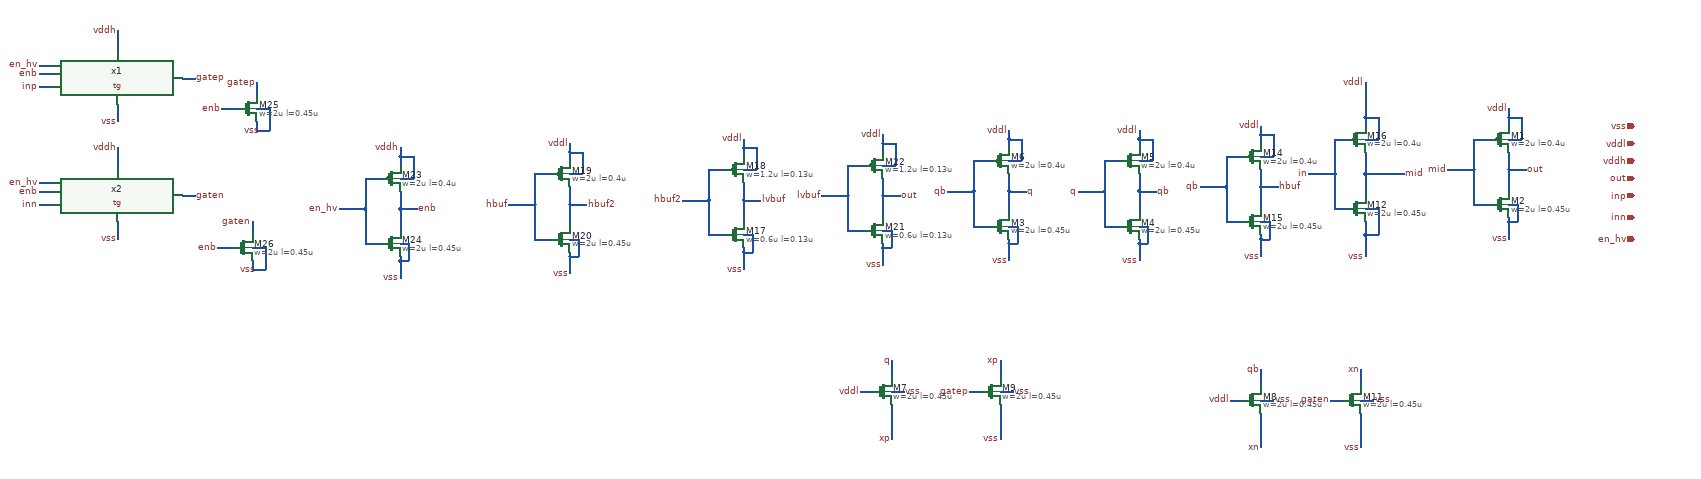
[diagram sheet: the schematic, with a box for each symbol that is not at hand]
v {xschem version=3.4.8RC file_version=1.3}
G {}
K {}
V {}
S {}
F {}
E {}
N 710 -410 710 -360 {lab=out
spice_ignore=true}
N 710 -290 710 -250 {lab=vss
spice_ignore=true}
N 710 -530 710 -510 {lab=vddl
spice_ignore=true}
N 630 -480 670 -480 {lab=mid
spice_ignore=true}
N 630 -410 630 -330 {lab=mid
spice_ignore=true}
N 630 -330 670 -330 {lab=mid
spice_ignore=true}
N 570 -410 630 -410 {lab=mid
spice_ignore=true}
N 630 -480 630 -410 {lab=mid
spice_ignore=true}
N 710 -480 740 -480 {lab=vddl
spice_ignore=true}
N 740 -530 740 -480 {lab=vddl
spice_ignore=true}
N 710 -530 740 -530 {lab=vddl
spice_ignore=true}
N 710 -550 710 -530 {lab=vddl
spice_ignore=true}
N 710 -330 730 -330 {lab=vss
spice_ignore=true}
N 730 -330 730 -290 {lab=vss
spice_ignore=true}
N 710 -290 730 -290 {lab=vss
spice_ignore=true}
N 710 -300 710 -290 {lab=vss
spice_ignore=true}
N 710 -410 750 -410 {lab=out
spice_ignore=true}
N 710 -450 710 -410 {lab=out
spice_ignore=true}
N 380 -400 380 -350 {
lab=mid
spice_ignore=true}
N 380 -530 380 -510 {
lab=vddl
spice_ignore=true}
N 380 -260 380 -210 {
lab=vss
spice_ignore=true}
N 380 -320 410 -320 {
lab=vss
spice_ignore=true}
N 310 -480 340 -480 {
lab=in
spice_ignore=true}
N 310 -400 310 -320 {
lab=in
spice_ignore=true}
N 310 -320 340 -320 {
lab=in
spice_ignore=true}
N 380 -480 410 -480 {
lab=vddl
spice_ignore=true}
N 410 -530 410 -480 {
lab=vddl
spice_ignore=true}
N 380 -530 410 -530 {
lab=vddl
spice_ignore=true}
N 410 -320 410 -260 {
lab=vss
spice_ignore=true}
N 380 -260 410 -260 {
lab=vss
spice_ignore=true}
N 250 -400 310 -400 {
lab=in
spice_ignore=true}
N 380 -400 470 -400 {
lab=mid
spice_ignore=true}
N 380 -610 380 -530 {
lab=vddl
spice_ignore=true}
N 380 -290 380 -260 {
lab=vss
spice_ignore=true}
N 310 -480 310 -400 {
lab=in
spice_ignore=true}
N 380 -450 380 -400 {
lab=mid
spice_ignore=true}
N -440 -360 -440 -310 {lab=q}
N -440 -240 -440 -200 {lab=vss}
N -440 -480 -440 -460 {lab=vddl}
N -520 -430 -480 -430 {lab=qb}
N -520 -360 -520 -280 {lab=qb}
N -520 -280 -480 -280 {lab=qb}
N -580 -360 -520 -360 {lab=qb}
N -520 -430 -520 -360 {lab=qb}
N -440 -430 -410 -430 {lab=vddl}
N -410 -480 -410 -430 {lab=vddl}
N -440 -480 -410 -480 {lab=vddl}
N -440 -500 -440 -480 {lab=vddl}
N -440 -280 -420 -280 {lab=vss}
N -420 -280 -420 -240 {lab=vss}
N -440 -240 -420 -240 {lab=vss}
N -440 -250 -440 -240 {lab=vss}
N -440 -360 -400 -360 {lab=q}
N -440 -400 -440 -360 {lab=q}
N -140 -360 -140 -310 {lab=qb}
N -140 -240 -140 -200 {lab=vss}
N -140 -480 -140 -460 {lab=vddl}
N -220 -430 -180 -430 {lab=q}
N -220 -360 -220 -280 {lab=q}
N -220 -280 -180 -280 {lab=q}
N -280 -360 -220 -360 {lab=q}
N -220 -430 -220 -360 {lab=q}
N -140 -430 -110 -430 {lab=vddl}
N -110 -480 -110 -430 {lab=vddl}
N -140 -480 -110 -480 {lab=vddl}
N -140 -500 -140 -480 {lab=vddl}
N -140 -280 -120 -280 {lab=vss}
N -120 -280 -120 -240 {lab=vss}
N -140 -240 -120 -240 {lab=vss}
N -140 -250 -140 -240 {lab=vss}
N -140 -360 -100 -360 {lab=qb}
N -140 -400 -140 -360 {lab=qb}
N -710 100 -680 100 {
lab=vss
}
N -780 100 -750 100 {
lab=vddl
}
N -710 130 -710 210 {
lab=xp
}
N -710 30 -710 70 {lab=q}
N -460 100 -430 100 {
lab=vss
}
N -530 100 -500 100 {
lab=gatep
}
N -460 130 -460 210 {
lab=vss
}
N -460 30 -460 70 {lab=xp}
N 140 120 170 120 {
lab=vss
}
N 70 120 100 120 {
lab=vddl
}
N 140 150 140 230 {
lab=xn
}
N 140 50 140 90 {lab=qb}
N 370 120 400 120 {
lab=vss
}
N 300 120 330 120 {
lab=gaten
}
N 370 150 370 230 {
lab=vss
}
N 370 50 370 90 {lab=xn}
N 140 -370 140 -320 {lab=hbuf}
N 140 -250 140 -210 {lab=vss}
N 140 -490 140 -470 {lab=vddl}
N 60 -440 100 -440 {lab=qb}
N 60 -370 60 -290 {lab=qb}
N 60 -290 100 -290 {lab=qb}
N 0 -370 60 -370 {lab=qb}
N 60 -440 60 -370 {lab=qb}
N 140 -440 170 -440 {lab=vddl}
N 170 -490 170 -440 {lab=vddl}
N 140 -490 170 -490 {lab=vddl}
N 140 -510 140 -490 {lab=vddl}
N 140 -290 160 -290 {lab=vss}
N 160 -290 160 -250 {lab=vss}
N 140 -250 160 -250 {lab=vss}
N 140 -260 140 -250 {lab=vss}
N 140 -370 180 -370 {lab=hbuf}
N 140 -410 140 -370 {lab=hbuf}
N -1050 -340 -1050 -290 {lab=lvbuf}
N -1050 -220 -1050 -180 {lab=vss}
N -1050 -460 -1050 -440 {lab=vddl}
N -1130 -410 -1090 -410 {lab=hbuf2}
N -1130 -340 -1130 -260 {lab=hbuf2}
N -1130 -260 -1090 -260 {lab=hbuf2}
N -1190 -340 -1130 -340 {lab=hbuf2}
N -1130 -410 -1130 -340 {lab=hbuf2}
N -1050 -410 -1020 -410 {lab=vddl}
N -1020 -460 -1020 -410 {lab=vddl}
N -1050 -460 -1020 -460 {lab=vddl}
N -1050 -480 -1050 -460 {lab=vddl}
N -1050 -260 -1030 -260 {lab=vss}
N -1030 -260 -1030 -220 {lab=vss}
N -1050 -220 -1030 -220 {lab=vss}
N -1050 -230 -1050 -220 {lab=vss}
N -1050 -340 -1010 -340 {lab=lvbuf}
N -1050 -380 -1050 -340 {lab=lvbuf}
N -1450 -330 -1450 -280 {lab=hbuf2}
N -1450 -210 -1450 -170 {lab=vss}
N -1450 -450 -1450 -430 {lab=vddl}
N -1530 -400 -1490 -400 {lab=hbuf}
N -1530 -330 -1530 -250 {lab=hbuf}
N -1530 -250 -1490 -250 {lab=hbuf}
N -1590 -330 -1530 -330 {lab=hbuf}
N -1530 -400 -1530 -330 {lab=hbuf}
N -1450 -400 -1420 -400 {lab=vddl}
N -1420 -450 -1420 -400 {lab=vddl}
N -1450 -450 -1420 -450 {lab=vddl}
N -1450 -470 -1450 -450 {lab=vddl}
N -1450 -250 -1430 -250 {lab=vss}
N -1430 -250 -1430 -210 {lab=vss}
N -1450 -210 -1430 -210 {lab=vss}
N -1450 -220 -1450 -210 {lab=vss}
N -1450 -330 -1410 -330 {lab=hbuf2}
N -1450 -370 -1450 -330 {lab=hbuf2}
N -730 -350 -730 -300 {lab=out}
N -730 -230 -730 -190 {lab=vss}
N -730 -470 -730 -450 {lab=vddl}
N -810 -420 -770 -420 {lab=lvbuf}
N -810 -350 -810 -270 {lab=lvbuf}
N -810 -270 -770 -270 {lab=lvbuf}
N -870 -350 -810 -350 {lab=lvbuf}
N -810 -420 -810 -350 {lab=lvbuf}
N -730 -420 -700 -420 {lab=vddl}
N -700 -470 -700 -420 {lab=vddl}
N -730 -470 -700 -470 {lab=vddl}
N -730 -490 -730 -470 {lab=vddl}
N -730 -270 -710 -270 {lab=vss}
N -710 -270 -710 -230 {lab=vss}
N -730 -230 -710 -230 {lab=vss}
N -730 -240 -730 -230 {lab=vss}
N -730 -350 -690 -350 {lab=out}
N -730 -390 -730 -350 {lab=out}
N -1840 -320 -1840 -270 {lab=enb}
N -1840 -200 -1840 -160 {lab=vss}
N -1840 -440 -1840 -420 {lab=vddh}
N -1920 -390 -1880 -390 {lab=en_hv}
N -1920 -320 -1920 -240 {lab=en_hv}
N -1920 -240 -1880 -240 {lab=en_hv}
N -1980 -320 -1920 -320 {lab=en_hv}
N -1920 -390 -1920 -320 {lab=en_hv}
N -1840 -390 -1810 -390 {lab=vddh}
N -1810 -440 -1810 -390 {lab=vddh}
N -1840 -440 -1810 -440 {lab=vddh}
N -1840 -460 -1840 -440 {lab=vddh}
N -1840 -240 -1820 -240 {lab=vss}
N -1820 -240 -1820 -200 {lab=vss}
N -1840 -200 -1820 -200 {lab=vss}
N -1840 -210 -1840 -200 {lab=vss}
N -1840 -320 -1800 -320 {lab=enb}
N -1840 -360 -1840 -320 {lab=enb}
N -2490 -730 -2490 -680 {lab=vddh}
N -2490 -560 -2490 -520 {lab=vss}
N -2670 -600 -2640 -600 {lab=inp}
N -2670 -630 -2640 -630 {lab=enb}
N -2670 -650 -2640 -650 {lab=en_hv}
N -2340 -620 -2310 -620 {lab=gatep}
N -2490 -460 -2490 -410 {lab=vddh}
N -2490 -290 -2490 -250 {lab=vss}
N -2670 -330 -2640 -330 {lab=inn}
N -2670 -360 -2640 -360 {lab=enb}
N -2670 -380 -2640 -380 {lab=en_hv}
N -2340 -350 -2310 -350 {lab=gaten}
N -2170 -610 -2170 -580 {lab=gatep}
N -2250 -550 -2210 -550 {lab=enb}
N -2170 -550 -2140 -550 {lab=vss}
N -2140 -550 -2140 -500 {lab=vss}
N -2170 -500 -2140 -500 {lab=vss}
N -2170 -520 -2170 -500 {lab=vss}
N -2180 -290 -2180 -260 {lab=gaten}
N -2260 -230 -2220 -230 {lab=enb}
N -2180 -230 -2150 -230 {lab=vss}
N -2150 -230 -2150 -180 {lab=vss}
N -2180 -180 -2150 -180 {lab=vss}
N -2180 -200 -2180 -180 {lab=vss}
C {iopin.sym} 1000 -470 0 0 {name=p11 lab=vddl}
C {iopin.sym} 1000 -390 0 0 {name=p1 lab=out
}
C {iopin.sym} 1000 -510 0 0 {name=p3 lab=vss}
C {iopin.sym} 1000 -350 0 0 {name=p5 lab=inp}
C {lab_pin.sym} 250 -400 0 0 {name=p6 sig_type=std_logic lab=in
spice_ignore=true}
C {lab_pin.sym} 710 -550 0 0 {name=p8 sig_type=std_logic lab=vddl
spice_ignore=true}
C {lab_pin.sym} 710 -250 0 0 {name=p9 sig_type=std_logic lab=vss
spice_ignore=true}
C {sg13cmos5l_pr/sg13_hv_nmos.sym} 360 -320 0 0 {name=M12
l=0.45u
w=2u
 ng=1
 m=1
  mm_ok=1
 model=sg13_hv_nmos
spiceprefix=X
spice_ignore=true}
C {sg13cmos5l_pr/sg13_hv_pmos.sym} 360 -480 0 0 {name=M16
l=0.4u
w=2u
 ng=1
 m=4
  mm_ok=1
 model=sg13_hv_pmos
spiceprefix=X
spice_ignore=true}
C {lab_pin.sym} 380 -210 3 0 {name=p4 sig_type=std_logic lab=vss
spice_ignore=true}
C {lab_pin.sym} 470 -400 2 0 {name=p15 sig_type=std_logic lab=mid
spice_ignore=true}
C {lab_pin.sym} 380 -610 0 0 {name=p2 sig_type=std_logic lab=vddl
spice_ignore=true}
C {lab_pin.sym} 570 -410 0 0 {name=p14 sig_type=std_logic lab=mid
spice_ignore=true}
C {lab_pin.sym} 750 -410 2 0 {name=p7 sig_type=std_logic lab=out
spice_ignore=true}
C {sg13cmos5l_pr/sg13_hv_pmos.sym} 690 -480 0 0 {name=M1
l=0.4u
w=2u
 ng=1
 m=2
  mm_ok=1
 model=sg13_hv_pmos
spiceprefix=X
spice_ignore=true}
C {sg13cmos5l_pr/sg13_hv_nmos.sym} 690 -330 0 0 {name=M2
l=0.45u
w=2u
 ng=1
 m=1
  mm_ok=1
 model=sg13_hv_nmos
spiceprefix=X
spice_ignore=true}
C {lab_pin.sym} -580 -360 0 0 {name=p10 sig_type=std_logic lab=qb}
C {lab_pin.sym} -400 -360 2 0 {name=p12 sig_type=std_logic lab=q}
C {lab_pin.sym} -440 -500 0 0 {name=p13 sig_type=std_logic lab=vddl}
C {lab_pin.sym} -440 -200 0 0 {name=p16 sig_type=std_logic lab=vss}
C {lab_pin.sym} -280 -360 0 0 {name=p17 sig_type=std_logic lab=q}
C {lab_pin.sym} -100 -360 2 0 {name=p18 sig_type=std_logic lab=qb}
C {lab_pin.sym} -140 -500 0 0 {name=p19 sig_type=std_logic lab=vddl}
C {lab_pin.sym} -140 -200 0 0 {name=p20 sig_type=std_logic lab=vss}
C {sg13cmos5l_pr/sg13_hv_nmos.sym} -730 100 0 0 {name=M7
l=0.45u
w=2u
 ng=1
 m=4
  mm_ok=1
 model=sg13_hv_nmos
spiceprefix=X
}
C {lab_pin.sym} -710 210 3 0 {name=p22 sig_type=std_logic lab=xp
}
C {lab_pin.sym} -780 100 0 0 {name=p27 sig_type=std_logic lab=vddl
}
C {lab_pin.sym} -710 30 0 0 {name=p21 sig_type=std_logic lab=q}
C {lab_pin.sym} -680 100 2 0 {name=p28 sig_type=std_logic lab=vss
}
C {sg13cmos5l_pr/sg13_hv_nmos.sym} -480 100 0 0 {name=M9
l=0.45u
w=2u
 ng=1
 m=4
  mm_ok=1
 model=sg13_hv_nmos
spiceprefix=X
}
C {lab_pin.sym} -460 210 3 0 {name=p29 sig_type=std_logic lab=vss
}
C {lab_pin.sym} -530 100 0 0 {name=p30 sig_type=std_logic lab=gatep
}
C {lab_pin.sym} -460 30 0 0 {name=p31 sig_type=std_logic lab=xp}
C {lab_pin.sym} -430 100 2 0 {name=p32 sig_type=std_logic lab=vss
}
C {sg13cmos5l_pr/sg13_hv_nmos.sym} 120 120 0 0 {name=M8
l=0.45u
w=2u
 ng=1
 m=4
  mm_ok=1
 model=sg13_hv_nmos
spiceprefix=X
}
C {lab_pin.sym} 140 230 3 0 {name=p23 sig_type=std_logic lab=xn
}
C {lab_pin.sym} 70 120 0 0 {name=p24 sig_type=std_logic lab=vddl
}
C {lab_pin.sym} 140 50 0 0 {name=p25 sig_type=std_logic lab=qb}
C {lab_pin.sym} 170 120 2 0 {name=p26 sig_type=std_logic lab=vss
}
C {sg13cmos5l_pr/sg13_hv_nmos.sym} 350 120 0 0 {name=M11
l=0.45u
w=2u
 ng=1
 m=4
  mm_ok=1
 model=sg13_hv_nmos
spiceprefix=X
}
C {lab_pin.sym} 370 230 3 0 {name=p37 sig_type=std_logic lab=vss
}
C {lab_pin.sym} 300 120 0 0 {name=p38 sig_type=std_logic lab=gaten
}
C {lab_pin.sym} 370 50 0 0 {name=p39 sig_type=std_logic lab=xn}
C {lab_pin.sym} 400 120 2 0 {name=p40 sig_type=std_logic lab=vss
}
C {lab_pin.sym} 0 -370 0 0 {name=p45 sig_type=std_logic lab=qb}
C {lab_pin.sym} 180 -370 2 0 {name=p46 sig_type=std_logic lab=hbuf}
C {lab_pin.sym} 140 -510 0 0 {name=p47 sig_type=std_logic lab=vddl}
C {lab_pin.sym} 140 -210 0 0 {name=p48 sig_type=std_logic lab=vss}
C {sg13cmos5l_pr/sg13_lv_nmos.sym} -1070 -260 0 0 {name=M17
l=0.13u
w=0.6u
ng=1
m=1
mm_ok=1
model=sg13_lv_nmos
spiceprefix=X
}
C {sg13cmos5l_pr/sg13_lv_pmos.sym} -1070 -410 0 0 {name=M18
l=0.13u
w=1.2u
ng=1
m=1
mm_ok=1
model=sg13_lv_pmos
spiceprefix=X
}
C {lab_pin.sym} -1190 -340 0 0 {name=p49 sig_type=std_logic lab=hbuf2}
C {lab_pin.sym} -1010 -340 2 0 {name=p50 sig_type=std_logic lab=lvbuf}
C {lab_pin.sym} -1050 -480 0 0 {name=p51 sig_type=std_logic lab=vddl}
C {lab_pin.sym} -1050 -180 0 0 {name=p52 sig_type=std_logic lab=vss}
C {iopin.sym} 1000 -300 0 0 {name=p53 lab=inn
}
C {iopin.sym} 1000 -250 0 0 {name=p54 lab=en_hv
}
C {sg13cmos5l_pr/sg13_hv_nmos.sym} -460 -280 0 0 {name=M3
l=0.45u
w=2u
 ng=1
 m=1
  mm_ok=1
 model=sg13_hv_nmos
spiceprefix=X
}
C {sg13cmos5l_pr/sg13_hv_nmos.sym} -160 -280 0 0 {name=M4
l=0.45u
w=2u
 ng=1
 m=1
  mm_ok=1
 model=sg13_hv_nmos
spiceprefix=X
}
C {sg13cmos5l_pr/sg13_hv_pmos.sym} -160 -430 0 0 {name=M5
l=0.4u
w=2u
 ng=1
 m=2
  mm_ok=1
 model=sg13_hv_pmos
spiceprefix=X
}
C {sg13cmos5l_pr/sg13_hv_pmos.sym} -460 -430 0 0 {name=M6
l=0.4u
w=2u
 ng=1
 m=2
  mm_ok=1
 model=sg13_hv_pmos
spiceprefix=X
}
C {sg13cmos5l_pr/sg13_hv_pmos.sym} 120 -440 0 0 {name=M14
l=0.4u
w=2u
 ng=1
 m=2
  mm_ok=1
 model=sg13_hv_pmos
spiceprefix=X
}
C {sg13cmos5l_pr/sg13_hv_nmos.sym} 120 -290 0 0 {name=M15
l=0.45u
w=2u
 ng=1
 m=1
  mm_ok=1
 model=sg13_hv_nmos
spiceprefix=X
}
C {lab_pin.sym} -1590 -330 0 0 {name=p55 sig_type=std_logic lab=hbuf}
C {lab_pin.sym} -1410 -330 2 0 {name=p56 sig_type=std_logic lab=hbuf2}
C {lab_pin.sym} -1450 -470 0 0 {name=p57 sig_type=std_logic lab=vddl}
C {lab_pin.sym} -1450 -170 0 0 {name=p58 sig_type=std_logic lab=vss}
C {sg13cmos5l_pr/sg13_hv_pmos.sym} -1470 -400 0 0 {name=M19
l=0.4u
w=2u
 ng=1
 m=2
  mm_ok=1
 model=sg13_hv_pmos
spiceprefix=X
}
C {sg13cmos5l_pr/sg13_hv_nmos.sym} -1470 -250 0 0 {name=M20
l=0.45u
w=2u
 ng=1
 m=1
  mm_ok=1
 model=sg13_hv_nmos
spiceprefix=X
}
C {sg13cmos5l_pr/sg13_lv_nmos.sym} -750 -270 0 0 {name=M21
l=0.13u
w=0.6u
ng=1
m=1
mm_ok=1
model=sg13_lv_nmos
spiceprefix=X
}
C {sg13cmos5l_pr/sg13_lv_pmos.sym} -750 -420 0 0 {name=M22
l=0.13u
w=1.2u
ng=1
m=1
mm_ok=1
model=sg13_lv_pmos
spiceprefix=X
}
C {lab_pin.sym} -690 -350 2 0 {name=p60 sig_type=std_logic lab=out}
C {lab_pin.sym} -730 -490 0 0 {name=p61 sig_type=std_logic lab=vddl}
C {lab_pin.sym} -730 -190 0 0 {name=p62 sig_type=std_logic lab=vss}
C {lab_pin.sym} -870 -350 0 0 {name=p59 sig_type=std_logic lab=lvbuf}
C {iopin.sym} 1000 -430 0 0 {name=p63 lab=vddh}
C {lab_pin.sym} -1980 -320 0 0 {name=p64 sig_type=std_logic lab=en_hv}
C {lab_pin.sym} -1800 -320 2 0 {name=p65 sig_type=std_logic lab=enb}
C {lab_pin.sym} -1840 -460 0 0 {name=p66 sig_type=std_logic lab=vddh}
C {lab_pin.sym} -1840 -160 0 0 {name=p67 sig_type=std_logic lab=vss}
C {sg13cmos5l_pr/sg13_hv_pmos.sym} -1860 -390 0 0 {name=M23
l=0.4u
w=2u
 ng=1
 m=2
  mm_ok=1
 model=sg13_hv_pmos
spiceprefix=X
}
C {sg13cmos5l_pr/sg13_hv_nmos.sym} -1860 -240 0 0 {name=M24
l=0.45u
w=2u
 ng=1
 m=1
  mm_ok=1
 model=sg13_hv_nmos
spiceprefix=X
}
C {tg.sym} -2490 -620 0 0 {name=x1}
C {lab_pin.sym} -2490 -730 0 0 {name=p68 sig_type=std_logic lab=vddh}
C {lab_pin.sym} -2490 -520 0 0 {name=p69 sig_type=std_logic lab=vss}
C {lab_pin.sym} -2670 -630 0 0 {name=p70 sig_type=std_logic lab=enb}
C {lab_pin.sym} -2670 -600 0 0 {name=p71 sig_type=std_logic lab=inp}
C {lab_pin.sym} -2310 -620 2 0 {name=p72 sig_type=std_logic lab=gatep}
C {lab_pin.sym} -2670 -650 0 0 {name=p73 sig_type=std_logic lab=en_hv}
C {tg.sym} -2490 -350 0 0 {name=x2}
C {lab_pin.sym} -2490 -460 0 0 {name=p74 sig_type=std_logic lab=vddh}
C {lab_pin.sym} -2490 -250 0 0 {name=p75 sig_type=std_logic lab=vss}
C {lab_pin.sym} -2670 -360 0 0 {name=p76 sig_type=std_logic lab=enb}
C {lab_pin.sym} -2670 -330 0 0 {name=p77 sig_type=std_logic lab=inn}
C {lab_pin.sym} -2310 -350 2 0 {name=p78 sig_type=std_logic lab=gaten}
C {lab_pin.sym} -2670 -380 0 0 {name=p79 sig_type=std_logic lab=en_hv}
C {sg13cmos5l_pr/sg13_hv_nmos.sym} -2190 -550 0 0 {name=M25
l=0.45u
w=2u
 ng=1
 m=1
  mm_ok=1
 model=sg13_hv_nmos
spiceprefix=X
}
C {lab_pin.sym} -2160 -500 3 0 {name=p80 sig_type=std_logic lab=vss}
C {lab_pin.sym} -2170 -610 1 0 {name=p81 sig_type=std_logic lab=gatep}
C {lab_pin.sym} -2250 -550 0 0 {name=p82 sig_type=std_logic lab=enb}
C {sg13cmos5l_pr/sg13_hv_nmos.sym} -2200 -230 0 0 {name=M26
l=0.45u
w=2u
 ng=1
 m=1
  mm_ok=1
 model=sg13_hv_nmos
spiceprefix=X
}
C {lab_pin.sym} -2170 -180 3 0 {name=p83 sig_type=std_logic lab=vss}
C {lab_pin.sym} -2180 -290 1 0 {name=p84 sig_type=std_logic lab=gaten}
C {lab_pin.sym} -2260 -230 0 0 {name=p85 sig_type=std_logic lab=enb}
